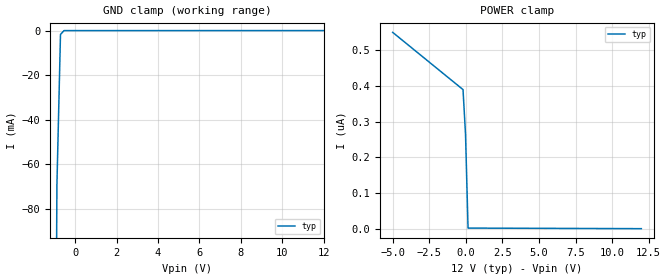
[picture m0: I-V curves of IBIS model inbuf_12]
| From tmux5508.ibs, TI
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| inbuf_12
[Model]   inbuf_12
Model_type   Input
Vinl = 0.7
Vinh = 1.2
|   typ   min   max
C_comp   1.008417e-12   NA   NA
[Voltage Range]   12   NA   NA
[Temperature Range]   27   NA   NA
[Power Clamp Reference]   12   NA   NA
[GND Clamp Reference]   0   NA   NA
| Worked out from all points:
|   GND clamp passes 1 mA (typ) near -0.63 V on its own axis
[GND Clamp]
|   Voltage   I(typ)   I(min)   I(max)
-5V       -13.02A    NA         NA
-1.051V   -346.1mA   NA         NA
-878.8mV  -69.04mA   NA         NA
-707.1mV  -1.724mA   NA         NA
-535.4mV  -7.76uA    NA         NA
12V       192.5nA    NA         NA
[POWER Clamp]
|   Voltage   I(typ)   I(min)   I(max)
-5V       550.7nA    NA         NA
-191.9mV  390.2nA    NA         NA
-20.2mV   264.2nA    NA         NA
151.5mV   1.52nA     NA         NA
12V       -50.97pA   NA         NA
